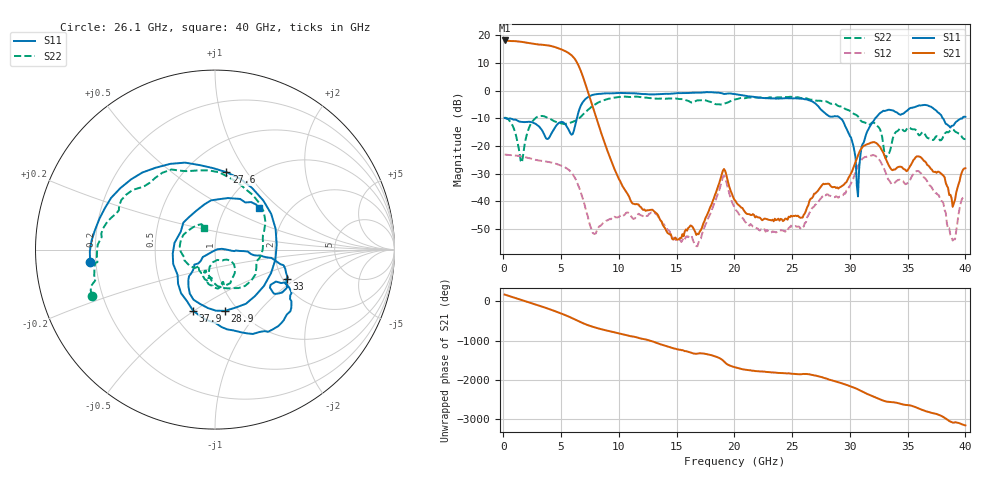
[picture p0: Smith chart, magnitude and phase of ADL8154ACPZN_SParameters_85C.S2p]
! Analog Devices, Inc."
! Device:	ADL8154ACPZN
! Description:	"10 MHz to 6 GHz, Wideband, Low Noise Amplifier"
! Conditions:	Vdd = 5.0 V
!		IDQ = 125 mA
!		Pin = -25 dBm
!		Operating Temperature = +85 C (at package bottom)
! Product validation unit SN30 soldered down to Evaluation Board as shown on ADL8154-EVALZ User Guide. Board loss de-embedded from S21 magnitude.  All other RF measurements reference to RF coaxial connector.
! Frequency (GHz)	S11_Mag (dB)	S11_Phase (deg)	S21_Mag (dB)	S21_Phase (deg)	S12_Mag (dB)	S12_Phase (deg)	S22_Mag (dB)	S22_Phase (deg)
#  GHZ  S  DB  R 50
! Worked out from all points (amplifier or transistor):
!   400 points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, 110 MHz to 40 GHz, reference 50 ohm
!   highest |S21| = 18.1 dB at 110 MHz (marker M1)
!   |S21| within 3 dB of that: start of sweep to 4.876 GHz
!   unconditionally stable (mu >= 1): start of sweep to end of sweep
!   at 6.708 GHz: K = 9.34, MAG = 9.2 dB, |S12| = -36.7 dB
!   at 20.11 GHz: K = 910.67, MAG = -31.0 dB, |S12| = -43.0 dB
!   at 40 GHz: K = 864.86, MAG = -27.4 dB, |S12| = -37.9 dB
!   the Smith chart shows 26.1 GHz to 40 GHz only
!   S11 on the Smith chart (normalised r, x): 26.1 GHz: 0.18, -0.05; 27.6 GHz: 0.76, +0.81; 28.9 GHz: 0.87, -0.68; 33 GHz: 2.10, -0.83; 37.9 GHz: 0.63, -0.49; 40 GHz: 1.42, +0.74
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0.11  -9.88 -179.0  18.14 170.2  -23.11 -6.0  -9.77 168.5
0.61  -10.03 155.8  17.95 122.9  -23.27 -44.5  -11.28 121.6
1.01  -10.45 140.9  17.89 85.4  -23.36 -74.5  -14.95 82.0
1.81  -11.35 112.8  17.46 9.9  -23.96 -135.8  -20.35 -116.7
2.209  -11.22 96.5  17.22 -27.6  -24.36 -166.7  -13.57 -166.6
2.809  -12.04 56.0  16.80 -83.7  -25.00 146.8  -9.83 145.3
3.709  -17.27 -60.3  16.43 -172.0  -25.62 75.1  -9.59 83.4
4.509  -13.06 156.0  15.69 103.4  -26.32 6.8  -11.20 27.9
5.309  -11.89 64.5  14.39 12.8  -27.59 -66.1  -12.02 -52.3
6.009  -15.64 -78.8  12.36 -76.6  -30.22 -140.0  -11.27 -128.1
6.808  -4.62 130.1  6.02 172.1  -38.05 124.8  -8.98 165.6
7.808  -1.44 46.6  -6.75 64.0  -51.61 -22.6  -5.30 82.4
13.407  -1.30 173.4  -45.09 6.1  -45.55 1.3  -2.90 169.7
20.105  -1.27 13.5  -39.88 115.3  -43.01 114.2  -3.13 -6.8
26.103  -3.10 -174.3  -44.33 -51.4  -47.76 -52.2  -2.71 -159.5
26.803  -4.03 147.0  -38.34 -77.9  -42.12 -81.1  -3.34 -170.6
27.603  -7.22 81.6  -34.06 -134.5  -38.28 -138.0  -3.82 175.6
28.903  -9.22 -80.8  -34.96 107.0  -38.41 107.3  -5.32 140.5
33.002  -7.33 -22.0  -23.57 -19.2  -28.60 -17.7  -22.91 -99.8
33.402  -6.88 -28.2  -27.24 -43.7  -32.42 -37.9  -22.53 -50.6
37.901  -8.84 -109.8  -29.97 -34.9  -39.77 -27.5  -17.90 -133.2
40  -9.44 43.5  -28.02 80.2  -37.94 64.0  -17.44 118.4
